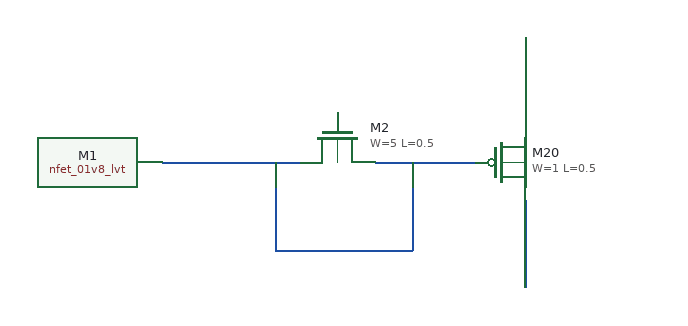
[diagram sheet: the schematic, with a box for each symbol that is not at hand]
v {xschem version=3.1.0 file_version=1.2
}
G {}
K {}
V {}
S {}
E {}
N 250 -200 360 -200 {
lab=#net1}
N 420 -200 500 -200 {
lab=#net1}
N 340 -200 340 -130 {
lab=#net1}
N 340 -130 450 -130 {
lab=#net1}
N 450 -200 450 -130 {
lab=#net1}
N 540 -300 540 -230 {}
N 540 -170 540 -100 {}
C {sky130_fd_pr/nfet_01v8_lvt.sym} 220 -220 3 1 {name=M1
L=0.5
W=5
nf=1
mult=1
ad="'int((nf+1)/2) * W/nf * 0.29'" 
pd="'2*int((nf+1)/2) * (W/nf + 0.29)'"
as="'int((nf+2)/2) * W/nf * 0.29'" 
ps="'2*int((nf+2)/2) * (W/nf + 0.29)'"
nrd="'0.29 / W'" nrs="'0.29 / W'"
sa=0 sb=0 sd=0
model=nfet_01v8_lvt
spiceprefix=X
}
C {sky130_fd_pr/nfet_01v8_lvt.sym} 390 -220 3 1 {name=M2
L=0.5
W=5
nf=1
mult=1
ad="'int((nf+1)/2) * W/nf * 0.29'" 
pd="'2*int((nf+1)/2) * (W/nf + 0.29)'"
as="'int((nf+2)/2) * W/nf * 0.29'" 
ps="'2*int((nf+2)/2) * (W/nf + 0.29)'"
nrd="'0.29 / W'" nrs="'0.29 / W'"
sa=0 sb=0 sd=0
model=nfet_01v8_lvt
spiceprefix=X
}
C {sky130_fd_pr/pfet_01v8.sym} 520 -200 0 0 {name=M20
L=0.5
W=1
nf=1
mult=1
ad="'int((nf+1)/2) * W/nf * 0.29'" 
pd="'2*int((nf+1)/2) * (W/nf + 0.29)'"
as="'int((nf+2)/2) * W/nf * 0.29'" 
ps="'2*int((nf+2)/2) * (W/nf + 0.29)'"
nrd="'0.29 / W'" nrs="'0.29 / W'"
sa=0 sb=0 sd=0
model=pfet_01v8
spiceprefix=X
}
